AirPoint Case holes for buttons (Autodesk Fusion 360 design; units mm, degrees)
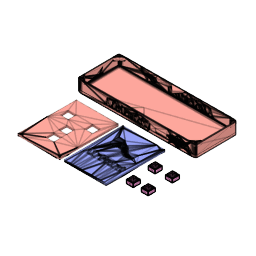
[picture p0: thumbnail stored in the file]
description: Part Number
part number: 2026-06-10-16-40-13-328
part number: 2026-06-10-16-40-15-996
part number: 2026-06-10-16-40-16-208
part number: 2026-06-10-16-40-16-226
part number: 2026-06-10-16-40-16-292
part number: 2026-06-10-16-40-16-296
part number: 2026-06-10-16-40-16-960
part number: 2026-06-10-16-40-16-966
part number: 2026-06-10-16-40-17-080
part number: 2026-06-10-16-40-17-086
part number: 2026-06-10-16-40-17-108
part number: 2026-06-10-16-40-17-114
part number: 2026-06-10-16-40-17-122
base_mesh_feature "Base Mesh Feature1"
base_mesh_feature "Base Mesh Feature1"
base_mesh_feature "Base Mesh Feature1"
base_mesh_feature "Base Mesh Feature1"
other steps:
create_component "CreateComponent1"
create_component "CreateComponent1"
create_component "CreateComponent1"
create_component "CreateComponent2"
create_component "CreateComponent1"
create_component "CreateComponent3"
create_component "CreateComponent1"
create_component "CreateComponent4"
create_component "CreateComponent1"
create_component "CreateComponent5"
create_component "CreateComponent6"
create_component "CreateComponent7"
